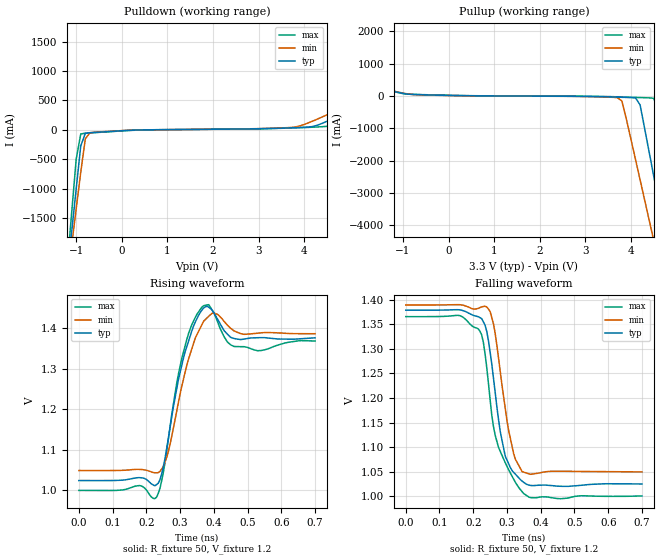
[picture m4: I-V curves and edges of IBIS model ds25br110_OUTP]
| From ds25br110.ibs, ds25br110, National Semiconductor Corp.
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[Model]   ds25br110_OUTP
Model_type Output
Polarity Non-Inverting
Vref=1.2
Vmeas=1.2
Rref=50   | 100 Ohms Across Outputs OUTP and OUTN
Cref=0p
C_comp   1.2pF   1.2pF   1.2pF
[Temperature Range]   25   85   -40
[Voltage Range]   3.3   3.0   3.6
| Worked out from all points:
|   slope of the pulldown table from 0 to 0.495 V, typ, clamps not added: 33.8 ohm
|   slope of the pullup table from 0 to 0.495 V, typ, clamps not added: 46 ohm
|   rising waveform, R_fixture 50, V_fixture 1.2: 20-80 % time 45.8ps typ, 52.4ps min, 40.9ps max; typ from 1.02 V to 1.38 V
|   falling waveform, R_fixture 50, V_fixture 1.2: 20-80 % time 43.7ps typ, 43ps min, 57ps max; typ from 1.38 V to 1.02 V
[Pullup]
|Vtable   I(typ)   I(min)   I(max)
-3.6V     2.055A     2.034A     2.086A
-2.8V     983mA      1.113A     895.5mA
-2.3V     587.1mA    581.7mA    613.5mA
-1V       81.1mA     89.85mA    72.44mA
3.7V      -35.27mA   -49.74mA   -25.22mA
3.8V      -39.6mA    -150.7mA   -29.88mA
4.2V      -273mA     -2.588A    -48.33mA
4.5V      -2.48A     -4.467A    -70.59mA
4.6V      -3.22A     -5.095A    -499.3mA
4.7V      -3.962A    -5.722A    -1.418A
5V        -6.191A    -7.602A    -4.198A
7.2V      -22.46A    -21.34A    -24.56A
[Pulldown]
|V(pulldown)   I(typ)   I(min)   I(max)
-3.6V     -20.28A    -17.63A    -24.6A
-1.2V     -2.482A    -2.594A    -2.344A
-1.1V     -1.742A    -1.968A    -1.418A
-1V       -1.004A    -1.344A    -498.9mA
-900mV    -273.8mA   -723mA     -70.13mA
-800mV    -60.55mA   -152.7mA   -56.97mA
-700mV    -48.78mA   -50.88mA   -52.29mA
3.7V      34.14mA    40.16mA    30.96mA
4.7V      218.9mA    327mA      101.6mA
5.9V      761.9mA    1.237A     619.9mA
6.4V      1.398A     1.817A     907.4mA
7.2V      2.477A     2.746A     2.106A
[Ramp]
|   typ   min   max
dV/dt_r   212m/36p   201m/43p   219m/37p
dV/dt_f   212m/36p   201m/43p   219m/37p
R_load=50
[Rising Waveform]
R_fixture=50
V_fixture=1.2
V_fixture_min=1.218
V_fixture_max=1.1817
0s        1.024V     1.049V     999.9mV
180ps     1.031V     1.052V     1.012V
230ps     1.014V     1.043V     983.1mV
260ps     1.102V     1.081V     1.096V
305ps     1.309V     1.257V     1.325V
335ps     1.394V     1.35V      1.409V
370ps     1.45V      1.417V     1.455V
400ps     1.438V     1.437V     1.438V
460ps     1.374V     1.393V     1.355V
700ps     1.376V     1.386V     1.368V
[Falling Waveform]
R_fixture=50
V_fixture=1.2
V_fixture_min=1.218
V_fixture_max=1.1817
0s        1.379V     1.389V     1.365V
155ps     1.38V      1.39V      1.368V
215ps     1.365V     1.382V     1.34V
230ps     1.355V     1.386V     1.313V
245ps     1.317V     1.381V     1.23V
265ps     1.211V     1.331V     1.124V
295ps     1.081V     1.178V     1.068V
320ps     1.049V     1.086V     1.034V
350ps     1.028V     1.049V     1.005V
700ps     1.025V     1.05V      1.001V
